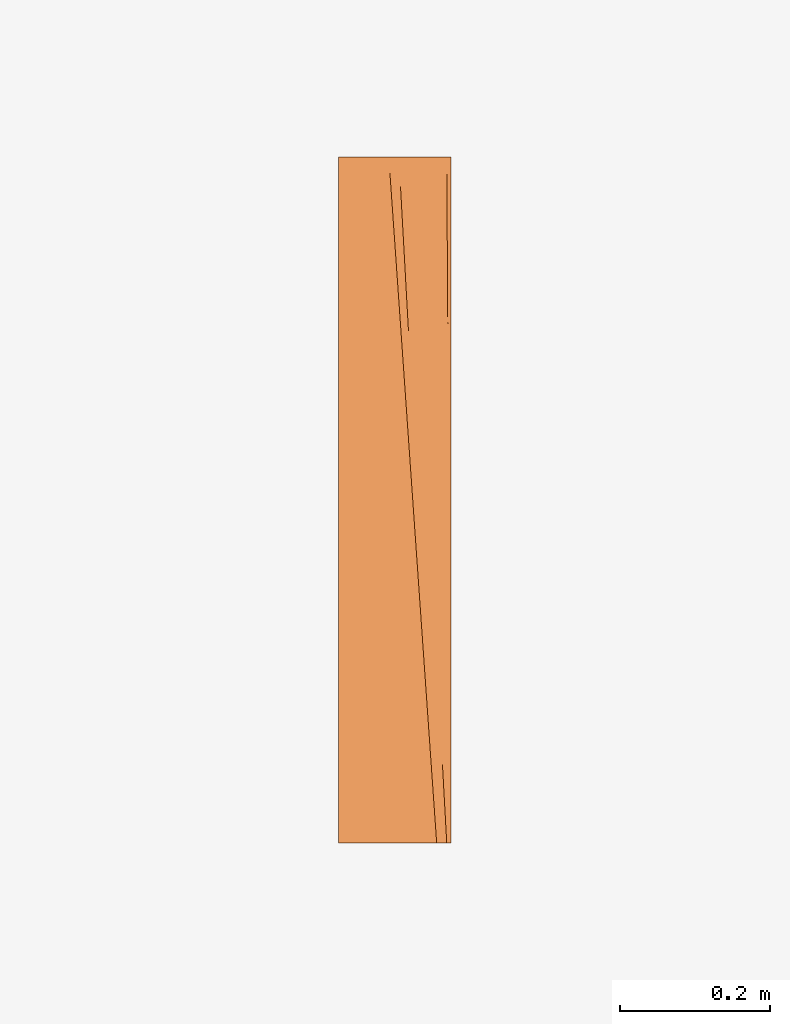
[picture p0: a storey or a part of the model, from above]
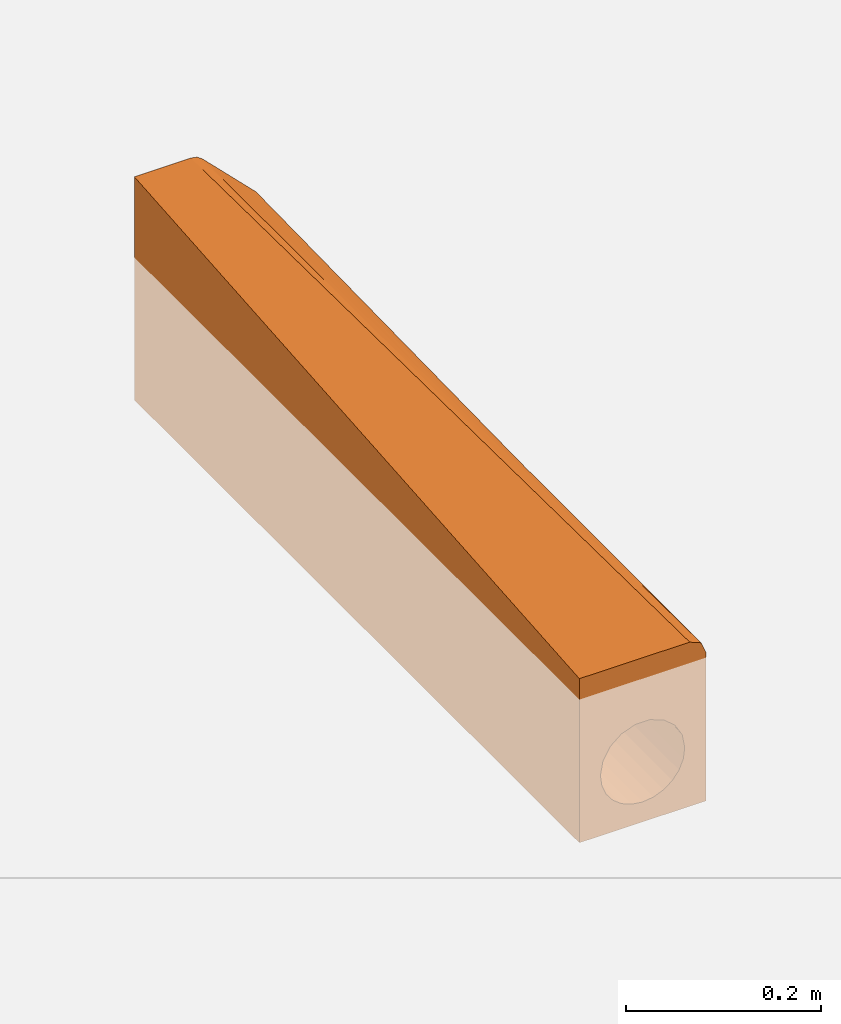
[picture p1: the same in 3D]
Properties of the parts of a building model (IFC2X3)

# File
Description: ViewDefinition [CoordinationView]
File name: 7939 - RH drop kerb - 1000mm LG.ifc
Time: 2013-09-02T12:32:22
Written by: Autodesk Revit 2013
Made in: 20120221_2030(x64)

# IfcProject, Project Number
LongName: Project Name; Phase: Project Status

# IfcSite, Default
RefLatitude: 42, 21, 30, 344238; RefLongitude: -71, -3, -35, -194702; RefElevation: 0 mm

# IfcBuilding
Pset_BuildingCommon - NumberOfStoreys: 1
Other - Project Number: Project Number; Project Status: Project Status; Project Issue Date: Issue Date; Client Name: Owner; Project Address: ## Street City, State Zip; Project Name: Project Name

# IfcBuildingStorey, Level 1
LongName: Level 1; Elevation: 0 mm
Constraints - Elevation Base: 0; Elevation: 0 mm
Graphics - Line Weight: 1; Line Pattern: Center; Symbol at End 1 Default: no; Symbol: M_Level Head - Circle: M_Level Head - Circle; Symbol at End 2 Default: yes; Color: 0
Dimensions - Computation Height: 0 mm
Identity Data - Name: Level 1; Structural: no; Building Story: yes

# IfcBuildingElementProxy: 7939 - RH drop kerb - 1000mm LG, Civil-Drainage-Channel-ACO-KerbDrain-SP280:7939 - RH drop kerb - 1000mm LG:7939 - RH drop kerb - 1000mm LG:311063
In: Level 1
Material: ACO Polymer Concrete.
Phasing - Phase Created: New Construction
Constraints - Moves With Nearby Elements: no; Level: Level: Level 1
Dimensions - Volume: 21635036 mm3; AccessDepth: 2000 mm; Void Depth: -180 mm; Void Width: 150 mm; Void Length: 915 mm; Endcap void: 205 mm; Access hole: 2 mm
Pset_BuildingElementProxyCommon - Reference: 7939 - RH drop kerb - 1000mm LG
Identity Data - OmniClass Number: 23.70.50.24; OmniClass Title: Rainwater Removal; URL: www.aco.co.uk; Installation guidelines: http://www.aco.co.uk/download.php?id=120; Telephone: +44 (0)1462 816666; Fax: +44 (0)1462 815895; Product brochure: http://www.aco.co.uk/download.php?id=120; Product Page URL: http://www.aco.co.uk/product_detail.php?id=3; e-mail Technical: technical@aco.co.uk; Model Description: Combined kerb and drainage system; Maintenance guidelines: http://www.aco.co.uk/download.php?id=120; Address: ACO Business Park, Hitchin Road, Shefford, Bedfordshire, United Kingdom SG17 5TE; e-mail Sales: customersupport@aco.co.uk; Manufacturer: ACO Technologies plc - ACO Water Management Division; Cost: 0; Assembly Description: Rain Water Drainage; Assembly Code: D2040; Product Code: 7939; Model: ACO KerbDrain SP280; Type Comments: ACO KerbDrain SP280 splayed right-hand drop kerb unit 1000mm long; Price: POA - contact ACO
General - SerialNumber: 0.000000; TagNumber: 0.000000
Other - CreatedBy: www.aco.co.uk; Revision: 1
Data - Channel C.S.A: 0.02 to 0.008m²; Concrete Surround Volume - Load Class A 15 - D 400 - Grass or Asphalt Pavement: N/A; Drainage Slot Intake area: N/A; Invert Depth: 255/180mm; Load Class: A 15 - D 400; Connection Pipe O.D: N/A; Hydraulic Performance: http://www.aco.co.uk/download.php?id=120; Product Weight: 44.6 Kg; Product Dimensions: 1000mm x 150mm x 280/205mm (LxWxH); Installation - Concrete Grade: Refer to brochure; Product Standard: BS EN 1433:2002, CE marked, Kitemarked; Concrete Surround Volume - Load Class A 15 - D 400 - Concrete Pavement: N/A; Drainage Slot Width: N/A; ACO Hydraulic Design Software: http://www.acodesign.co.uk
Materials and Finishes - Channel Colour: Grey; Access Cover/Frame Colour: N/A; Access Cover/Frame Finish: N/A; End Cap Colour: N/A; Connection Pipe Material: N/A; Access Cover/Frame Material: N/A; Connection Pipe Material Colour: N/A; Channel Material: Vienite® Synthetic Resin Concrete; End Cap Material: N/A
Green Building Properties - Channel Recyclable: Fully recyclable; Channel Recycled Material Content: 20% minimum; Access Cover/Frame Recycled Material Content: N/A; Access Cover/Frame Recyclable: N/A; End Cap Recyclable: N/A; End Cap Recycled Material Content: N/A
Construction - SP280-500: no; Closing end cap: no; Centre Stone: no; SP280 - 1000: no; LH transition unit: no; LH drop kerb: no; RH transition unit: no; perforated centre stone: no; LH inlet/outlet end cap: no; RH drop kerb: yes; Access Unit: no; RH inlet/outlet end cap: no

# IfcOpeningElement: Recess (2)
In: Level 1
Dimensions - Thickness: 400 mm; Area: 151470000 mm2; Volume: 60563295000 mm3; Perimeter: 51360 mm
Constraints - Height Offset From Level: 0 mm; Related to Mass: no; Level: Level: Level 1; Room Bounding: yes
Phasing - Phase Created: New Construction
Structural - Enable Analytical Model: no; Structural: no
Construction - Function: 0; Default Thickness: 400 mm
Materials and Finishes - Structural Material: Plant
Graphics - Coarse Scale Fill Color: 0
Analytical Properties - Absorptance: 0.1; Roughness: 1

# IfcSlab: Floor:Generic Floor - 400mm, Floor:Generic Floor - 400mm:193825
In: Level 1
PredefinedType: FLOOR; Material: Plant 400 mm
Dimensions - Thickness: 400 mm; Area: 151470000 mm2; Volume: 60563295000 mm3; Perimeter: 51360 mm
Constraints - Height Offset From Level: 0 mm; Related to Mass: no; Level: Level: Level 1; Room Bounding: yes
Phasing - Phase Created: New Construction
Structural - Enable Analytical Model: no; Structural: no
Pset_SlabCommon - Reference: Generic Floor - 400mm; IsExternal: no; LoadBearing: yes
Construction - Function: 0; Default Thickness: 400 mm
Materials and Finishes - Structural Material: Plant
Graphics - Coarse Scale Fill Color: 0
Analytical Properties - Absorptance: 0.1; Roughness: 1
